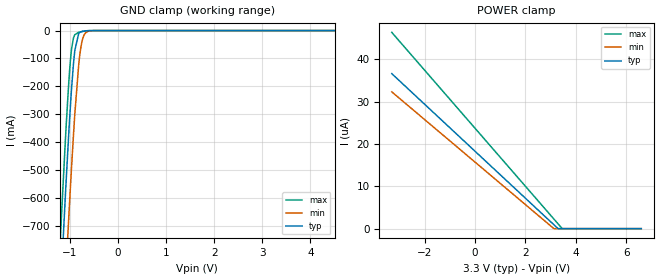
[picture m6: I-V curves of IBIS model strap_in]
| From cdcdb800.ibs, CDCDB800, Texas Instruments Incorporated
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[Model]   strap_in
Model_type   Input
Vinl = 0.85
Vinh = 2.3
|   typ   min   max
C_comp   0.85pF   0.8pF   0.9pF
[Voltage Range]   3.3   3.135   3.465
[Temperature Range]   27   125   -40
[Power Clamp Reference]   3.3   3.135   3.465
[GND Clamp Reference]   0   0   0
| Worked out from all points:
|   GND clamp passes 1 mA (typ) near -0.67 V on its own axis
[GND Clamp]
|   Voltage   I(typ)   I(min)   I(max)
-3.3V     -9.039A    -9.284A    -8.888A
-1.191V   -935.6mA   -1.251A    -732.1mA
-1.162V   -831.3mA   -1.146A    -628.1mA
-1.092V   -595.2mA   -907mA     -396.1mA
-1.023V   -375mA     -677.2mA   -191.6mA
-973.5mV  -235mA     -521.6mA   -82.67mA
-894.3mV  -70.35mA   -296.7mA   -14.68mA
-815.1mV  -11.06mA   -123.5mA   -6.197mA
-765.6mV  -4.099mA   -56.26mA   -4.378mA
-716.1mV  -1.933mA   -21.53mA   -2.594mA
-557.7mV  -100.1uA   -739.2uA   -78.64uA
6.6V      0A         0A         0A
[POWER Clamp]
|   Voltage   I(typ)   I(min)   I(max)
-3.3V     36.61uA    32.31uA    46.35uA
3.125V    960.8nA    40.29nA    2.319uA
3.293V    26.75nA    0A         1.166uA
3.462V    0A         0A         12.44nA
6.6V      0A         0A         0A
